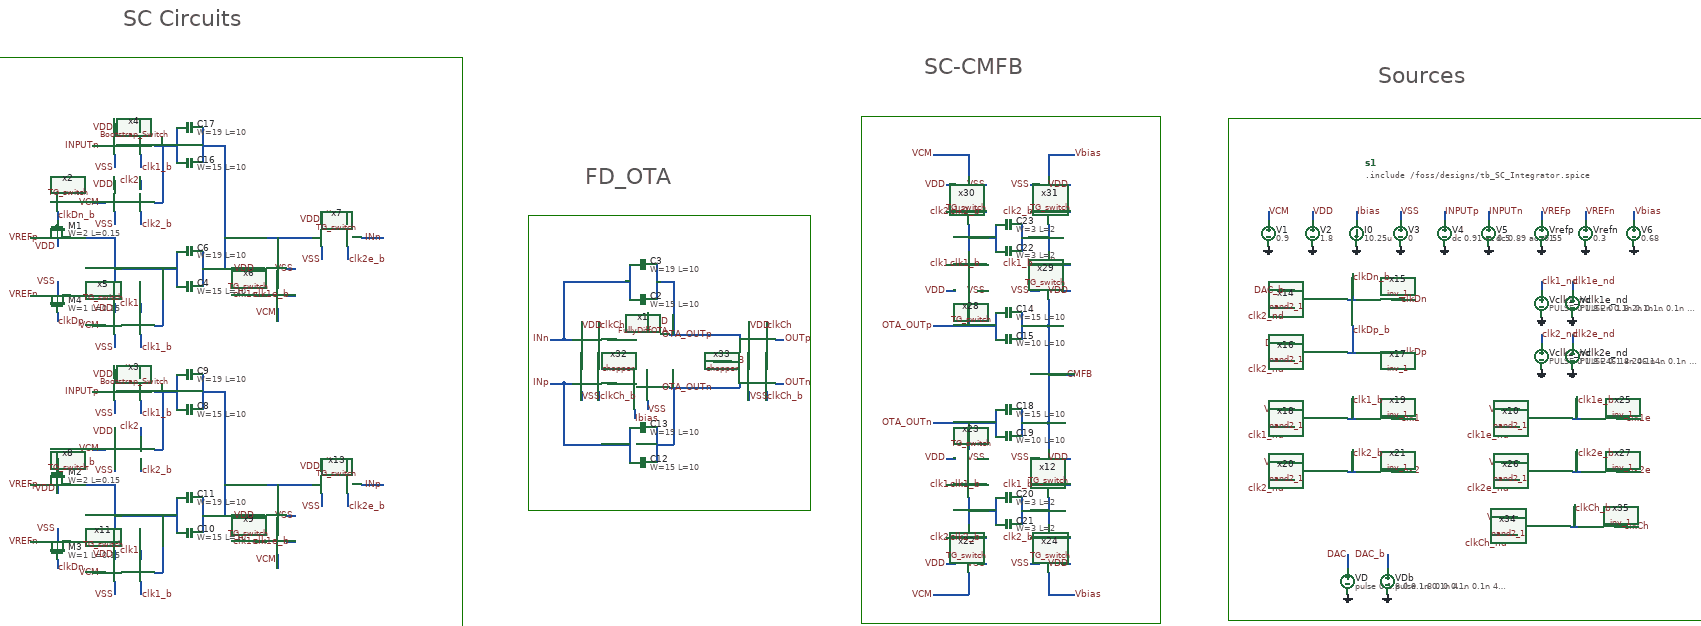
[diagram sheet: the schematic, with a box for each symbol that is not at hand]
v {xschem version=3.4.8RC file_version=1.3}
G {}
K {}
V {}
S {}
F {}
E {}
L 4 -1670 -770 -510 -770 {}
L 4 -510 -770 -510 570 {}
L 4 -1530 570 -510 570 {}
L 4 -1670 -770 -1670 570 {}
L 4 -1670 570 -1530 570 {}
P 4 5 1230 -630 2320 -630 2320 510 1230 510 1230 -630 {}
P 4 7 -360 -410 200 -410 280 -410 280 260 -330 260 -360 260 -360 -410 {}
P 4 5 395 -635 1075 -635 1075 515 395 515 395 -635 {}
T {Sources} 1570 -740 0 0 1.5 1.5 {}
T {FD_OTA} -230 -510 0 0 1.5 1.5 {}
T {SC Circuits} -1280 -870 0 0 1.5 1.5 {}
T {SC-CMFB} 540 -760 0 0 1.5 1.5 {}
N 1320 -420 1320 -400 {lab=VCM}
N 1420 -420 1420 -400 {lab=VDD}
N 1520 -420 1520 -400 {lab=Ibias}
N 1620 -420 1620 -400 {lab=VSS}
N 1720 -420 1720 -400 {lab=INPUTp}
N 1820 -420 1820 -400 {lab=INPUTn}
N 1940 -420 1940 -400 {lab=VREFp}
N 2040 -420 2040 -400 {lab=VREFn}
N 1500 -220 1520 -220 {lab=clkDn_b}
N 1340 -240 1380 -240 {lab=DAC_bar}
N 1360 -200 1380 -200 {lab=clk2_nd}
N 1360 -200 1360 -180 {lab=clk2_nd}
N 1600 -220 1630 -220 {lab=clkDn}
N 1340 -120 1380 -120 {lab=DAC}
N 1360 -80 1380 -80 {lab=clk2_nd}
N 1360 -80 1360 -60 {lab=clk2_nd}
N 1600 -100 1630 -100 {lab=clkDp}
N 1340 30 1380 30 {lab=VDD}
N 1360 70 1380 70 {lab=clk1_nd}
N 1360 70 1360 90 {lab=clk1_nd}
N 1600 50 1630 50 {lab=clk1}
N 1340 150 1380 150 {lab=VDD}
N 1360 190 1380 190 {lab=clk2_nd}
N 1360 190 1360 210 {lab=clk2_nd}
N 1600 170 1630 170 {lab=clk2}
N 1940 -260 1940 -240 {lab=clk1_nd}
N 2010 -260 2010 -240 {lab=clk1e_nd}
N 1850 30 1890 30 {lab=VDD}
N 1870 70 1890 70 {lab=clk1e_nd}
N 1870 70 1870 90 {lab=clk1e_nd}
N 2110 50 2140 50 {lab=clk1e}
N 1850 150 1890 150 {lab=VDD}
N 1870 190 1890 190 {lab=clk2e_nd}
N 1870 190 1870 210 {lab=clk2e_nd}
N 2110 170 2140 170 {lab=clk2e}
N 1940 -140 1940 -120 {lab=clk2_nd}
N 2010 -140 2010 -120 {lab=clk2e_nd}
N 1500 360 1500 390 {lab=DAC}
N 1590 360 1590 390 {lab=DAC_bar}
N 1500 -100 1520 -100 {lab=clkDp_b}
N 1500 50 1520 50 {lab=clk1_b}
N 1500 170 1520 170 {lab=clk2_b}
N 2010 50 2030 50 {lab=clk1e_b}
N 2010 170 2030 170 {lab=clk2e_b}
N 1510 0 1510 50 {lab=clk1_b}
N 1510 120 1510 170 {lab=clk2_b}
N 2020 0 2020 50 {lab=clk1e_b}
N 2020 120 2020 170 {lab=clk2e_b}
N 1510 -280 1510 -220 {lab=clkDn_b}
N 1510 -160 1510 -100 {lab=clkDp_b}
N 2150 -420 2150 -400 {lab=Vbias}
N 60 -80 100 -80 {lab=CMFB}
N -90 10 -90 30 {lab=VSS}
N -90 -190 -90 -170 {lab=VDD}
N -120 30 -120 50 {lab=Ibias}
N -40 -140 -20 -140 {lab=OTA_OUTp}
N -40 -20 -20 -20 {lab=OTA_OUTn}
N -1100 -570 -1050 -570 {lab=#net1}
N -1050 -550 -1050 -480 {lab=#net1}
N -1050 -570 -1050 -550 {lab=#net1}
N -1300 -550 -1300 -520 {lab=VSS}
N -1240 -620 -1240 -600 {lab=clk1}
N -1350 -570 -1320 -570 {lab=INPUTn}
N -1300 -420 -1300 -390 {lab=VSS}
N -1240 -490 -1240 -470 {lab=clk2}
N -1350 -440 -1320 -440 {lab=VCM}
N -1050 -480 -1050 -440 {lab=#net1}
N -1100 -290 -1050 -290 {lab=#net1}
N -1300 -140 -1300 -110 {lab=VSS}
N -1240 -210 -1240 -190 {lab=clk1}
N -1350 -160 -1320 -160 {lab=VCM}
N -1050 -440 -1050 -290 {lab=#net1}
N -1210 -570 -1160 -570 {lab=#net2}
N -1210 -290 -1160 -290 {lab=#net3}
N -1050 -360 -960 -360 {lab=#net1}
N -980 -230 -960 -230 {lab=clk1e}
N -930 -200 -930 -170 {lab=VCM}
N -930 -360 -930 -310 {lab=#net1}
N -960 -360 -940 -360 {lab=#net1}
N -940 -360 -850 -360 {lab=#net1}
N -830 -340 -830 -310 {lab=VSS}
N -770 -410 -770 -390 {lab=clk2e}
N -740 -360 -690 -360 {lab=INn}
N -170 -260 -130 -260 {lab=INn}
N -30 -220 -30 -140 {lab=OTA_OUTp}
N -30 -20 -30 70 {lab=OTA_OUTn}
N -180 -130 -160 -130 {lab=#net4}
N -180 -30 -160 -30 {lab=#net5}
N -20 -140 0 -140 {lab=OTA_OUTp}
N -20 -20 0 -20 {lab=OTA_OUTn}
N -1100 -10 -1050 -10 {lab=#net6}
N -1050 10 -1050 80 {lab=#net6}
N -1050 -10 -1050 10 {lab=#net6}
N -1300 10 -1300 40 {lab=VSS}
N -1240 -60 -1240 -40 {lab=clk1}
N -1350 -10 -1320 -10 {lab=INPUTp}
N -1300 140 -1300 170 {lab=VSS}
N -1240 70 -1240 90 {lab=clk2}
N -1350 120 -1320 120 {lab=VCM}
N -1050 80 -1050 120 {lab=#net6}
N -1100 270 -1050 270 {lab=#net6}
N -1300 420 -1300 450 {lab=VSS}
N -1240 350 -1240 370 {lab=clk1}
N -1350 400 -1320 400 {lab=VCM}
N -1050 120 -1050 270 {lab=#net6}
N -1210 -10 -1160 -10 {lab=#net7}
N -1210 270 -1160 270 {lab=#net8}
N -1050 200 -960 200 {lab=#net6}
N -930 200 -930 250 {lab=#net6}
N -960 200 -940 200 {lab=#net6}
N -940 200 -850 200 {lab=#net6}
N -830 220 -830 250 {lab=VSS}
N -770 150 -770 170 {lab=clk2e}
N -740 200 -690 200 {lab=INp}
N -1350 -360 -1300 -360 {lab=#net3}
N -1300 -360 -1300 -230 {lab=#net3}
N -1350 -230 -1300 -230 {lab=#net3}
N -1300 -290 -1210 -290 {lab=#net3}
N -1430 140 -1430 160 {lab=clkDp_b}
N -1490 200 -1460 200 {lab=VREFp}
N -1430 300 -1430 330 {lab=VSS}
N -1430 370 -1430 390 {lab=clkDn}
N -1490 330 -1460 330 {lab=VREFn}
N -1350 200 -1300 200 {lab=#net8}
N -1300 200 -1300 330 {lab=#net8}
N -1350 330 -1300 330 {lab=#net8}
N -1300 270 -1210 270 {lab=#net8}
N -1190 -570 -1190 -440 {lab=#net2}
N -1210 -440 -1190 -440 {lab=#net2}
N -1190 -10 -1190 120 {lab=#net7}
N -1210 120 -1190 120 {lab=#net7}
N -1210 400 -1190 400 {lab=#net8}
N -1190 270 -1190 400 {lab=#net8}
N -1190 -290 -1190 -160 {lab=#net3}
N -1210 -160 -1190 -160 {lab=#net3}
N -910 -290 -890 -290 {lab=VSS}
N -70 -260 -30 -260 {lab=OTA_OUTp}
N -30 -260 -30 -220 {lab=OTA_OUTp}
N -170 110 -130 110 {lab=INp}
N -30 70 -30 110 {lab=OTA_OUTn}
N -70 110 -30 110 {lab=OTA_OUTn}
N -1160 -610 -1160 -530 {lab=#net2}
N -1100 -610 -1100 -530 {lab=#net1}
N -1160 -330 -1160 -250 {lab=#net3}
N -1100 -330 -1100 -250 {lab=#net1}
N -1160 -50 -1160 30 {lab=#net7}
N -1100 -50 -1100 30 {lab=#net6}
N -1160 230 -1160 310 {lab=#net8}
N -1100 230 -1100 310 {lab=#net6}
N -130 -300 -130 -220 {lab=INn}
N -70 -300 -70 -220 {lab=OTA_OUTp}
N -130 70 -130 150 {lab=INp}
N -70 70 -70 150 {lab=OTA_OUTn}
N -1240 -550 -1240 -530 {lab=clk1_b}
N -1240 -530 -1240 -520 {lab=clk1_b}
N -1300 -620 -1300 -600 {lab=VDD}
N -1300 -60 -1300 -40 {lab=VDD}
N -1240 10 -1240 30 {lab=clk1_b}
N -1240 30 -1240 40 {lab=clk1_b}
N -1430 200 -1430 220 {lab=VDD}
N -1400 200 -1350 200 {lab=#net8}
N -1430 -420 -1430 -400 {lab=clkDn_b}
N -1490 -360 -1460 -360 {lab=VREFp}
N -1430 -360 -1430 -340 {lab=VDD}
N -1400 -360 -1350 -360 {lab=#net3}
N -1400 330 -1350 330 {lab=#net8}
N -1430 -260 -1430 -230 {lab=VSS}
N -1430 -190 -1430 -170 {lab=clkDp}
N -1490 -230 -1460 -230 {lab=VREFn}
N -1400 -230 -1350 -230 {lab=#net3}
N -980 -290 -960 -290 {lab=VDD}
N -910 -230 -890 -230 {lab=clk1e_b}
N -980 330 -960 330 {lab=clk1e}
N -930 360 -930 390 {lab=VCM}
N -910 270 -890 270 {lab=VSS}
N -980 270 -960 270 {lab=VDD}
N -910 330 -890 330 {lab=clk1e_b}
N -1300 -490 -1300 -470 {lab=VDD}
N -1300 -210 -1300 -190 {lab=VDD}
N -830 -410 -830 -390 {lab=VDD}
N -1300 70 -1300 90 {lab=VDD}
N -1300 350 -1300 370 {lab=VDD}
N -830 150 -830 170 {lab=VDD}
N -1240 -420 -1240 -390 {lab=clk2_b}
N -1240 -140 -1240 -110 {lab=clk1_b}
N -1240 140 -1240 170 {lab=clk2_b}
N -1240 420 -1240 450 {lab=clk1_b}
N -770 -340 -770 -310 {lab=clk2e_b}
N -770 220 -770 250 {lab=clk2e_b}
N 560 -160 580 -160 {lab=OTA_OUTp}
N 560 60 580 60 {lab=OTA_OUTn}
N 580 60 700 60 {lab=OTA_OUTn}
N 700 -190 700 -130 {lab=OTA_OUTp}
N 760 -190 760 -180 {lab=CMFB}
N 760 -180 760 -140 {lab=CMFB}
N 760 -140 760 -130 {lab=CMFB}
N 700 30 700 90 {lab=OTA_OUTn}
N 760 30 760 40 {lab=CMFB}
N 760 40 760 80 {lab=CMFB}
N 760 80 760 90 {lab=CMFB}
N 580 -160 700 -160 {lab=OTA_OUTp}
N 560 450 600 450 {lab=VCM}
N 590 200 610 200 {lab=clk1}
N 660 140 680 140 {lab=VSS}
N 590 140 610 140 {lab=VDD}
N 660 200 680 200 {lab=clk1_b}
N 640 60 640 120 {lab=OTA_OUTn}
N 850 200 870 200 {lab=clk1}
N 780 200 800 200 {lab=clk1_b}
N 820 60 820 120 {lab=CMFB}
N 850 140 870 140 {lab=VDD}
N 780 140 800 140 {lab=VSS}
N 590 320 610 320 {lab=clk2}
N 660 380 680 380 {lab=VSS}
N 590 380 610 380 {lab=VDD}
N 660 320 680 320 {lab=clk2_b}
N 850 320 870 320 {lab=clk2}
N 780 320 800 320 {lab=clk2_b}
N 850 380 870 380 {lab=VDD}
N 780 380 800 380 {lab=VSS}
N 600 450 640 450 {lab=VCM}
N 640 400 640 450 {lab=VCM}
N 820 450 880 450 {lab=Vbias}
N 820 400 820 450 {lab=Vbias}
N 640 230 640 290 {lab=#net9}
N 820 230 820 290 {lab=#net10}
N 700 230 700 290 {lab=#net9}
N 760 230 760 240 {lab=#net10}
N 760 240 760 280 {lab=#net10}
N 760 280 760 290 {lab=#net10}
N 640 260 700 260 {lab=#net9}
N 760 260 820 260 {lab=#net10}
N 560 -550 600 -550 {lab=VCM}
N 590 -300 610 -300 {lab=clk1}
N 660 -240 680 -240 {lab=VSS}
N 590 -240 610 -240 {lab=VDD}
N 660 -300 680 -300 {lab=clk1_b}
N 640 -220 640 -160 {lab=OTA_OUTp}
N 850 -300 870 -300 {lab=clk1}
N 780 -300 800 -300 {lab=clk1_b}
N 820 -220 820 -160 {lab=CMFB}
N 850 -240 870 -240 {lab=VDD}
N 780 -240 800 -240 {lab=VSS}
N 590 -420 610 -420 {lab=clk2}
N 660 -480 680 -480 {lab=VSS}
N 590 -480 610 -480 {lab=VDD}
N 660 -420 680 -420 {lab=clk2_b}
N 850 -420 870 -420 {lab=clk2}
N 780 -420 800 -420 {lab=clk2_b}
N 850 -480 870 -480 {lab=VDD}
N 780 -480 800 -480 {lab=VSS}
N 600 -550 640 -550 {lab=VCM}
N 640 -550 640 -500 {lab=VCM}
N 820 -550 880 -550 {lab=Vbias}
N 820 -550 820 -500 {lab=Vbias}
N 640 -390 640 -330 {lab=#net11}
N 820 -390 820 -330 {lab=#net12}
N 700 -390 700 -330 {lab=#net11}
N 760 -340 760 -330 {lab=#net12}
N 760 -380 760 -340 {lab=#net12}
N 760 -390 760 -380 {lab=#net12}
N 640 -360 700 -360 {lab=#net11}
N 760 -360 820 -360 {lab=#net12}
N 820 -160 820 60 {lab=CMFB}
N 820 -50 880 -50 {lab=CMFB}
N 760 60 820 60 {lab=CMFB}
N 760 -160 820 -160 {lab=CMFB}
N -280 -130 -260 -130 {lab=INn}
N -280 -30 -260 -30 {lab=INp}
N -280 -260 -170 -260 {lab=INn}
N -280 -260 -280 -130 {lab=INn}
N -280 -30 -280 110 {lab=INp}
N -280 110 -170 110 {lab=INp}
N -310 -30 -280 -30 {lab=INp}
N -310 -130 -280 -130 {lab=INn}
N 0 -140 120 -140 {lab=OTA_OUTp}
N 120 -140 120 -130 {lab=OTA_OUTp}
N 0 -20 120 -20 {lab=OTA_OUTn}
N 120 -30 120 -20 {lab=OTA_OUTn}
N 200 -130 220 -130 {lab=OUTp}
N 200 -30 220 -30 {lab=OUTn}
N -240 -170 -240 -150 {lab=VDD}
N -200 -170 -200 -150 {lab=clkCh}
N -240 -10 -240 10 {lab=VSS}
N -200 -10 -200 10 {lab=clkCh_b}
N 140 -170 140 -150 {lab=VDD}
N 180 -170 180 -150 {lab=clkCh}
N 140 -10 140 10 {lab=VSS}
N 180 -10 180 10 {lab=clkCh_b}
N 1845 275 1885 275 {lab=VDD}
N 1865 315 1885 315 {lab=clkCh_nd}
N 1865 315 1865 335 {lab=clkCh_nd}
N 2105 295 2135 295 {lab=clkCh}
N 2005 295 2025 295 {lab=clkCh_b}
N 2015 245 2015 295 {lab=clkCh_b}
C {vsource.sym} 1320 -370 0 0 {name=V1 value=0.9 savecurrent=false}
C {lab_wire.sym} 1420 -420 0 1 {name=p16 sig_type=std_logic lab=VDD}
C {vsource.sym} 1420 -370 0 0 {name=V2 value=1.8 savecurrent=false}
C {lab_wire.sym} 1520 -420 0 1 {name=p18 sig_type=std_logic lab=Ibias}
C {isource.sym} 1520 -370 0 0 {name=I0 value=10.25u}
C {lab_wire.sym} 1620 -420 0 1 {name=p21 sig_type=std_logic lab=VSS}
C {vsource.sym} 1620 -370 0 0 {name=V3 value=0 savecurrent=false
lab=VSS}
C {gnd.sym} 1320 -340 0 0 {name=l1 lab=0}
C {gnd.sym} 1420 -340 0 0 {name=l2 lab=0}
C {gnd.sym} 1520 -340 0 0 {name=l3 lab=0}
C {gnd.sym} 1620 -340 0 0 {name=l4 lab=0}
C {code_shown.sym} 1540 -530 0 0 {name=s1 only_toplevel=false value=".include /foss/designs/tb_SC_Integrator.spice"}
C {launcher.sym} 1340 -520 0 0 {name=h1
descr=backannotate
tclcommand="xschem annotate_op"}
C {lab_wire.sym} 1320 -420 0 1 {name=p11 sig_type=std_logic lab=VCM}
C {vsource.sym} 1720 -370 0 0 {name=V4 value="dc 0.91 ac 0.5" savecurrent=false
lab=INp}
C {vsource.sym} 1820 -370 0 0 {name=V5 value="dc 0.89 ac -0.5" savecurrent=false
lab=INn}
C {gnd.sym} 1720 -340 0 0 {name=l5 lab=0}
C {gnd.sym} 1820 -340 0 0 {name=l6 lab=0}
C {lab_wire.sym} 1820 -420 0 1 {name=p15 sig_type=std_logic lab=INPUTn}
C {lab_wire.sym} 1720 -420 0 1 {name=p17 sig_type=std_logic lab=INPUTp}
C {vsource.sym} 1940 -370 0 0 {name=Vrefp value=1.5 savecurrent=false}
C {gnd.sym} 1940 -340 0 0 {name=Vrefp1 lab=0}
C {lab_wire.sym} 1940 -420 0 1 {name=Vrefp2 sig_type=std_logic lab=VREFp}
C {vsource.sym} 2040 -370 0 0 {name=Vrefn value=0.3 savecurrent=false}
C {gnd.sym} 2040 -340 0 0 {name=Vrefp4 lab=0}
C {lab_wire.sym} 2040 -420 0 1 {name=Vrefp5 sig_type=std_logic lab=VREFn}
C {sky130_stdcells/nand2_1.sym} 1440 -220 0 0 {name=x14 VGND=VSS VNB=VSS VPB=VDD VPWR=VDD prefix=sky130_fd_sc_hd__ }
C {sky130_stdcells/inv_1.sym} 1560 -220 0 0 {name=x15 VGND=VSS VNB=VSS VPB=VDD VPWR=VDD prefix=sky130_fd_sc_hd__ }
C {lab_wire.sym} 1360 -180 0 0 {name=p23 sig_type=std_logic lab=clk2_nd}
C {lab_wire.sym} 1360 -240 0 0 {name=p24 sig_type=std_logic lab=DAC_b}
C {lab_wire.sym} 1360 -60 0 0 {name=p25 sig_type=std_logic lab=clk2_nd}
C {lab_wire.sym} 1360 -120 0 0 {name=p26 sig_type=std_logic lab=DAC}
C {lab_wire.sym} 1620 -220 2 0 {name=p32 sig_type=std_logic lab=clkDn}
C {lab_wire.sym} 1620 -100 2 0 {name=p33 sig_type=std_logic lab=clkDp}
C {lab_wire.sym} 1360 90 0 0 {name=p34 sig_type=std_logic lab=clk1_nd}
C {lab_wire.sym} 1360 30 0 0 {name=p35 sig_type=std_logic lab=VDD}
C {lab_wire.sym} 1360 210 0 0 {name=p36 sig_type=std_logic lab=clk2_nd}
C {lab_wire.sym} 1360 150 0 0 {name=p37 sig_type=std_logic lab=VDD}
C {lab_wire.sym} 1620 50 2 0 {name=p38 sig_type=std_logic lab=clk1}
C {lab_wire.sym} 1620 170 2 0 {name=p39 sig_type=std_logic lab=clk2}
C {vsource.sym} 1940 -210 0 1 {name=Vclk1_nd value="PULSE 0 1.8 2n 0.1n 0.1n 238n 488.28n" savecurrent=false}
C {gnd.sym} 1940 -180 0 0 {name=l7 lab=0}
C {lab_wire.sym} 1940 -260 0 1 {name=p58 sig_type=std_logic lab=clk1_nd}
C {vsource.sym} 2010 -210 0 0 {name=Vclk1e_nd value="PULSE 0 1.8 2n 0.1n 0.1n 237n 488.28n" savecurrent=false}
C {gnd.sym} 2010 -180 0 1 {name=l8 lab=0}
C {lab_wire.sym} 2010 -260 0 1 {name=p59 sig_type=std_logic lab=clk1e_nd}
C {lab_wire.sym} 1870 90 0 0 {name=p60 sig_type=std_logic lab=clk1e_nd}
C {lab_wire.sym} 1870 30 0 0 {name=p79 sig_type=std_logic lab=VDD}
C {lab_wire.sym} 1870 210 0 0 {name=p80 sig_type=std_logic lab=clk2e_nd}
C {lab_wire.sym} 1870 150 0 0 {name=p81 sig_type=std_logic lab=VDD}
C {lab_wire.sym} 2130 50 2 0 {name=p82 sig_type=std_logic lab=clk1e}
C {lab_wire.sym} 2130 170 2 0 {name=p83 sig_type=std_logic lab=clk2e}
C {vsource.sym} 1940 -90 0 1 {name=Vclk2_nd value="PULSE 0 1.8 246.14n 0.1n 0.1n 238n 488.28n" savecurrent=false}
C {gnd.sym} 1940 -60 0 0 {name=l9 lab=0}
C {lab_wire.sym} 1940 -140 0 1 {name=p84 sig_type=std_logic lab=clk2_nd}
C {vsource.sym} 2010 -90 0 0 {name=Vclk2e_nd value="PULSE 0 1.8 246.14n 0.1n 0.1n 237n 488.28n" savecurrent=false}
C {gnd.sym} 2010 -60 0 1 {name=l10 lab=0}
C {lab_wire.sym} 2010 -140 0 1 {name=p85 sig_type=std_logic lab=clk2e_nd}
C {lab_wire.sym} 1590 360 0 0 {name=p86 sig_type=std_logic lab=DAC_b}
C {lab_wire.sym} 1500 360 0 0 {name=p87 sig_type=std_logic lab=DAC}
C {vsource.sym} 1500 420 0 1 {name=VD value="pulse 0 1.8 0 0.1n 0.1n 488.18n 976.56n" savecurrent=false}
C {gnd.sym} 1500 450 0 0 {name=l11 lab=0}
C {vsource.sym} 1590 420 0 0 {name=VDb value="pulse 1.8 0 0 0.1n 0.1n 488.18n 976.56n" savecurrent=false}
C {gnd.sym} 1590 450 0 0 {name=l12 lab=0}
C {sky130_stdcells/nand2_1.sym} 1440 -100 0 0 {name=x16 VGND=VSS VNB=VSS VPB=VDD VPWR=VDD prefix=sky130_fd_sc_hd__ }
C {sky130_stdcells/inv_1.sym} 1560 -100 0 0 {name=x17 VGND=VSS VNB=VSS VPB=VDD VPWR=VDD prefix=sky130_fd_sc_hd__ }
C {sky130_stdcells/nand2_1.sym} 1440 50 0 0 {name=x18 VGND=VSS VNB=VSS VPB=VDD VPWR=VDD prefix=sky130_fd_sc_hd__ }
C {sky130_stdcells/inv_1.sym} 1560 50 0 0 {name=x19 VGND=VSS VNB=VSS VPB=VDD VPWR=VDD prefix=sky130_fd_sc_hd__ }
C {sky130_stdcells/nand2_1.sym} 1440 170 0 0 {name=x20 VGND=VSS VNB=VSS VPB=VDD VPWR=VDD prefix=sky130_fd_sc_hd__ }
C {sky130_stdcells/inv_1.sym} 1560 170 0 0 {name=x21 VGND=VSS VNB=VSS VPB=VDD VPWR=VDD prefix=sky130_fd_sc_hd__ }
C {sky130_stdcells/nand2_1.sym} 1950 50 0 0 {name=x10 VGND=VSS VNB=VSS VPB=VDD VPWR=VDD prefix=sky130_fd_sc_hd__ }
C {sky130_stdcells/inv_1.sym} 2070 50 0 0 {name=x25 VGND=VSS VNB=VSS VPB=VDD VPWR=VDD prefix=sky130_fd_sc_hd__ }
C {sky130_stdcells/nand2_1.sym} 1950 170 0 0 {name=x26 VGND=VSS VNB=VSS VPB=VDD VPWR=VDD prefix=sky130_fd_sc_hd__ }
C {sky130_stdcells/inv_1.sym} 2070 170 0 0 {name=x27 VGND=VSS VNB=VSS VPB=VDD VPWR=VDD prefix=sky130_fd_sc_hd__ }
C {lab_wire.sym} 1510 10 0 1 {name=p89 sig_type=std_logic lab=clk1_b}
C {lab_wire.sym} 1510 130 0 1 {name=p90 sig_type=std_logic lab=clk2_b}
C {lab_wire.sym} 2020 10 0 1 {name=p92 sig_type=std_logic lab=clk1e_b}
C {lab_wire.sym} 2020 130 0 1 {name=p93 sig_type=std_logic lab=clk2e_b}
C {lab_wire.sym} 1510 -150 0 1 {name=p70 sig_type=std_logic lab=clkDp_b}
C {lab_wire.sym} 1510 -270 0 1 {name=p71 sig_type=std_logic lab=clkDn_b}
C {lab_wire.sym} 2150 -420 0 1 {name=p9 sig_type=std_logic lab=Vbias}
C {vsource.sym} 2150 -370 0 0 {name=V6 value=0.68 savecurrent=false}
C {gnd.sym} 2150 -340 0 0 {name=l13 lab=0}
C {lab_wire.sym} -90 30 0 1 {name=p27 sig_type=std_logic lab=VSS}
C {lab_wire.sym} -90 -170 0 1 {name=p28 sig_type=std_logic lab=VDD}
C {lab_wire.sym} -120 50 0 1 {name=p29 sig_type=std_logic lab=Ibias}
C {lab_wire.sym} 70 -80 0 1 {name=p30 sig_type=std_logic lab=CMFB}
C {lab_wire.sym} -310 -30 3 0 {name=p2 sig_type=std_logic lab=INp}
C {lab_wire.sym} -310 -130 3 1 {name=p3 sig_type=std_logic lab=INn}
C {lab_wire.sym} 220 -130 0 1 {name=p4 sig_type=std_logic lab=OUTp}
C {lab_wire.sym} 220 -30 0 1 {name=p5 sig_type=std_logic lab=OUTn}
C {lab_wire.sym} -1300 -520 0 0 {name=p6 sig_type=std_logic lab=VSS}
C {lab_wire.sym} -1240 -620 2 1 {name=p7 sig_type=std_logic lab=clk1}
C {lab_wire.sym} -1330 -570 2 1 {name=p8 sig_type=std_logic lab=INPUTn}
C {lab_wire.sym} -1300 -390 0 0 {name=p47 sig_type=std_logic lab=VSS}
C {lab_wire.sym} -1240 -490 2 1 {name=p48 sig_type=std_logic lab=clk2}
C {lab_wire.sym} -1330 -440 2 1 {name=p49 sig_type=std_logic lab=VCM}
C {lab_wire.sym} -1300 -110 0 0 {name=p45 sig_type=std_logic lab=VSS}
C {lab_wire.sym} -1240 -210 2 1 {name=p46 sig_type=std_logic lab=clk1}
C {lab_wire.sym} -1330 -160 2 1 {name=p50 sig_type=std_logic lab=VCM}
C {lab_wire.sym} -890 -290 3 0 {name=p51 sig_type=std_logic lab=VSS}
C {lab_wire.sym} -970 -230 3 0 {name=p52 sig_type=std_logic lab=clk1e}
C {lab_wire.sym} -930 -190 1 1 {name=p53 sig_type=std_logic lab=VCM}
C {lab_wire.sym} -830 -310 0 0 {name=p54 sig_type=std_logic lab=VSS}
C {lab_wire.sym} -770 -410 2 1 {name=p55 sig_type=std_logic lab=clk2e}
C {lab_wire.sym} -690 -360 3 1 {name=p56 sig_type=std_logic lab=INn}
C {Analog/FullyDiffOTA.sym} -40 -260 0 0 {name=x1}
C {lab_wire.sym} -1300 40 0 0 {name=p31 sig_type=std_logic lab=VSS}
C {lab_wire.sym} -1240 -60 2 1 {name=p40 sig_type=std_logic lab=clk1}
C {lab_wire.sym} -1330 -10 2 1 {name=p41 sig_type=std_logic lab=INPUTp}
C {lab_wire.sym} -1300 170 0 0 {name=p42 sig_type=std_logic lab=VSS}
C {lab_wire.sym} -1240 70 2 1 {name=p43 sig_type=std_logic lab=clk2}
C {lab_wire.sym} -1330 120 2 1 {name=p57 sig_type=std_logic lab=VCM}
C {lab_wire.sym} -1300 450 0 0 {name=p61 sig_type=std_logic lab=VSS}
C {lab_wire.sym} -1240 350 2 1 {name=p62 sig_type=std_logic lab=clk1}
C {lab_wire.sym} -1330 400 2 1 {name=p63 sig_type=std_logic lab=VCM}
C {lab_wire.sym} -830 250 0 0 {name=p67 sig_type=std_logic lab=VSS}
C {lab_wire.sym} -770 150 2 1 {name=p68 sig_type=std_logic lab=clk2e}
C {lab_wire.sym} -690 200 3 1 {name=p69 sig_type=std_logic lab=INp}
C {lab_wire.sym} -1470 200 2 1 {name=p75 sig_type=std_logic lab=VREFp}
C {lab_wire.sym} -1430 300 3 1 {name=p76 sig_type=std_logic lab=VSS}
C {lab_wire.sym} -1430 390 0 1 {name=p77 sig_type=std_logic lab=clkDn}
C {lab_wire.sym} -1470 330 2 1 {name=p78 sig_type=std_logic lab=VREFn}
C {sky130_fd_pr/cap_mim_m3_2.sym} -1130 -530 1 1 {name=C16 model=cap_mim_m3_2 W=15 L=10 MF=3 spiceprefix=X}
C {sky130_fd_pr/cap_mim_m3_1.sym} -1130 -610 1 0 {name=C17 model=cap_mim_m3_1 W=19 L=10 MF=3 spiceprefix=X}
C {sky130_fd_pr/cap_mim_m3_2.sym} -100 -220 1 1 {name=C2 model=cap_mim_m3_2 W=15 L=10 MF=10 spiceprefix=X}
C {sky130_fd_pr/cap_mim_m3_1.sym} -100 -300 1 0 {name=C3 model=cap_mim_m3_1 W=19 L=10 MF=10 spiceprefix=X}
C {sky130_fd_pr/cap_mim_m3_2.sym} -1130 -250 1 1 {name=C4 model=cap_mim_m3_2 W=15 L=10 MF=3 spiceprefix=X}
C {sky130_fd_pr/cap_mim_m3_1.sym} -1130 -330 1 0 {name=C6 model=cap_mim_m3_1 W=19 L=10 MF=3 spiceprefix=X}
C {sky130_fd_pr/cap_mim_m3_2.sym} -1130 30 1 1 {name=C8 model=cap_mim_m3_2 W=15 L=10 MF=3 spiceprefix=X}
C {sky130_fd_pr/cap_mim_m3_1.sym} -1130 -50 1 0 {name=C9 model=cap_mim_m3_1 W=19 L=10 MF=3 spiceprefix=X}
C {sky130_fd_pr/cap_mim_m3_2.sym} -1130 310 1 1 {name=C10 model=cap_mim_m3_2 W=15 L=10 MF=3 spiceprefix=X}
C {sky130_fd_pr/cap_mim_m3_1.sym} -1130 230 1 0 {name=C11 model=cap_mim_m3_1 W=19 L=10 MF=3 spiceprefix=X}
C {sky130_fd_pr/cap_mim_m3_2.sym} -100 150 1 1 {name=C12 model=cap_mim_m3_2 W=15 L=10 MF=10 spiceprefix=X}
C {sky130_fd_pr/cap_mim_m3_1.sym} -100 70 1 0 {name=C13 model=cap_mim_m3_1 W=19 L=10 MF=10 spiceprefix=X}
C {lab_wire.sym} -1240 -520 0 1 {name=p91 sig_type=std_logic lab=clk1_b}
C {lab_wire.sym} -1300 -610 0 0 {name=p94 sig_type=std_logic lab=VDD}
C {lab_wire.sym} -1300 -50 0 0 {name=p95 sig_type=std_logic lab=VDD}
C {lab_wire.sym} -1240 40 0 1 {name=p96 sig_type=std_logic lab=clk1_b}
C {sky130_fd_pr/pfet_01v8.sym} -1430 180 1 0 {name=M2
W=2
L=0.15
nf=1
mult=1
ad="expr('int((@nf + 1)/2) * @W / @nf * 0.29')"
pd="expr('2*int((@nf + 1)/2) * (@W / @nf + 0.29)')"
as="expr('int((@nf + 2)/2) * @W / @nf * 0.29')"
ps="expr('2*int((@nf + 2)/2) * (@W / @nf + 0.29)')"
nrd="expr('0.29 / @W ')" nrs="expr('0.29 / @W ')"
sa=0 sb=0 sd=0
model=pfet_01v8
spiceprefix=X
}
C {lab_wire.sym} -1470 -360 2 1 {name=p44 sig_type=std_logic lab=VREFp}
C {sky130_fd_pr/pfet_01v8.sym} -1430 -380 1 0 {name=M1
W=2
L=0.15
nf=1
mult=1
ad="expr('int((@nf + 1)/2) * @W / @nf * 0.29')"
pd="expr('2*int((@nf + 1)/2) * (@W / @nf + 0.29)')"
as="expr('int((@nf + 2)/2) * @W / @nf * 0.29')"
ps="expr('2*int((@nf + 2)/2) * (@W / @nf + 0.29)')"
nrd="expr('0.29 / @W ')" nrs="expr('0.29 / @W ')"
sa=0 sb=0 sd=0
model=pfet_01v8
spiceprefix=X
}
C {lab_wire.sym} -1430 -340 1 1 {name=p73 sig_type=std_logic lab=VDD}
C {sky130_fd_pr/nfet_01v8.sym} -1430 350 3 0 {name=M3
W=1
L=0.15
nf=1 
mult=1
ad="expr('int((@nf + 1)/2) * @W / @nf * 0.29')"
pd="expr('2*int((@nf + 1)/2) * (@W / @nf + 0.29)')"
as="expr('int((@nf + 2)/2) * @W / @nf * 0.29')"
ps="expr('2*int((@nf + 2)/2) * (@W / @nf + 0.29)')"
nrd="expr('0.29 / @W ')" nrs="expr('0.29 / @W ')"
sa=0 sb=0 sd=0
model=nfet_01v8
spiceprefix=X
}
C {lab_wire.sym} -1430 -260 3 1 {name=p1 sig_type=std_logic lab=VSS}
C {lab_wire.sym} -1430 -170 0 1 {name=p98 sig_type=std_logic lab=clkDp}
C {lab_wire.sym} -1470 -230 2 1 {name=p99 sig_type=std_logic lab=VREFn}
C {sky130_fd_pr/nfet_01v8.sym} -1430 -210 3 0 {name=M4
W=1
L=0.15
nf=1 
mult=1
ad="expr('int((@nf + 1)/2) * @W / @nf * 0.29')"
pd="expr('2*int((@nf + 1)/2) * (@W / @nf + 0.29)')"
as="expr('int((@nf + 2)/2) * @W / @nf * 0.29')"
ps="expr('2*int((@nf + 2)/2) * (@W / @nf + 0.29)')"
nrd="expr('0.29 / @W ')" nrs="expr('0.29 / @W ')"
sa=0 sb=0 sd=0
model=nfet_01v8
spiceprefix=X
}
C {lab_wire.sym} -1430 -410 0 1 {name=p20 sig_type=std_logic lab=clkDn_b}
C {lab_wire.sym} -1430 150 0 1 {name=p72 sig_type=std_logic lab=clkDp_b}
C {Analog/Bootstrap_Switch.sym} -1270 -570 0 0 {name=x4 Wn=1.0 Wp=1.0 LL=0.15}
C {Analog/Bootstrap_Switch.sym} -1270 -10 0 0 {name=x3 Wn=1.0 Wp=1.0 LL=0.15}
C {Analog/TG_switch.sym} -930 -260 3 1 {name=x6 Wn=3.0 Wp=10.0 LL=0.35}
C {lab_wire.sym} -980 -290 1 1 {name=p74 sig_type=std_logic lab=VDD}
C {lab_wire.sym} -900 -230 1 1 {name=p97 sig_type=std_logic lab=clk1e_b}
C {lab_wire.sym} -890 270 3 0 {name=p64 sig_type=std_logic lab=VSS}
C {lab_wire.sym} -970 330 3 0 {name=p65 sig_type=std_logic lab=clk1e}
C {lab_wire.sym} -930 370 1 1 {name=p66 sig_type=std_logic lab=VCM}
C {Analog/TG_switch.sym} -930 300 3 1 {name=x9 Wn=3.0 Wp=10.0 LL=0.35}
C {lab_wire.sym} -980 270 1 1 {name=p100 sig_type=std_logic lab=VDD}
C {lab_wire.sym} -900 330 1 1 {name=p101 sig_type=std_logic lab=clk1e_b}
C {lab_wire.sym} -1300 -480 0 0 {name=p102 sig_type=std_logic lab=VDD}
C {lab_wire.sym} -1300 -200 0 0 {name=p103 sig_type=std_logic lab=VDD}
C {lab_wire.sym} -830 -400 0 0 {name=p104 sig_type=std_logic lab=VDD}
C {lab_wire.sym} -1300 80 0 0 {name=p105 sig_type=std_logic lab=VDD}
C {lab_wire.sym} -1300 360 0 0 {name=p106 sig_type=std_logic lab=VDD}
C {lab_wire.sym} -830 160 0 0 {name=p107 sig_type=std_logic lab=VDD}
C {Analog/TG_switch.sym} -1270 -440 0 0 {name=x2 Wn=3.0 Wp=10.0 LL=0.35}
C {Analog/TG_switch.sym} -1270 -160 0 0 {name=x5 Wn=3.0 Wp=10.0 LL=0.35}
C {Analog/TG_switch.sym} -1270 120 0 0 {name=x8 Wn=3.0 Wp=10.0 LL=0.35}
C {Analog/TG_switch.sym} -1270 400 0 0 {name=x11 Wn=3.0 Wp=10.0 LL=0.35}
C {lab_wire.sym} -1240 -390 0 1 {name=p109 sig_type=std_logic lab=clk2_b}
C {lab_wire.sym} -1240 -110 0 1 {name=p111 sig_type=std_logic lab=clk1_b}
C {lab_wire.sym} -1240 170 0 1 {name=p112 sig_type=std_logic lab=clk2_b}
C {lab_wire.sym} -1240 450 0 1 {name=p113 sig_type=std_logic lab=clk1_b}
C {Analog/TG_switch.sym} -800 -360 0 0 {name=x7 Wn=4.0 Wp=14.0 LL=0.35}
C {Analog/TG_switch.sym} -800 200 0 0 {name=x13 Wn=4.0 Wp=14.0 LL=0.35}
C {lab_wire.sym} -770 -310 0 1 {name=p114 sig_type=std_logic lab=clk2e_b}
C {lab_wire.sym} -770 250 0 1 {name=p115 sig_type=std_logic lab=clk2e_b}
C {lab_wire.sym} -1430 210 1 1 {name=p116 sig_type=std_logic lab=VDD}
C {lab_wire.sym} 560 -160 0 0 {name=p108 sig_type=std_logic lab=OTA_OUTp}
C {lab_wire.sym} 560 450 0 0 {name=p117 sig_type=std_logic lab=VCM}
C {lab_wire.sym} 860 -50 0 1 {name=p118 sig_type=std_logic lab=CMFB}
C {lab_wire.sym} 560 60 2 1 {name=p120 sig_type=std_logic lab=OTA_OUTn}
C {sky130_fd_pr/cap_mim_m3_2.sym} 730 -190 1 0 {name=C14 model=cap_mim_m3_2 W=15 L=10 MF=1 spiceprefix=X}
C {sky130_fd_pr/cap_mim_m3_1.sym} 730 -130 1 1 {name=C15 model=cap_mim_m3_1 W=10 L=10 MF=1 spiceprefix=X}
C {sky130_fd_pr/cap_mim_m3_2.sym} 730 30 1 0 {name=C18 model=cap_mim_m3_2 W=15 L=10 MF=1 spiceprefix=X}
C {sky130_fd_pr/cap_mim_m3_1.sym} 730 90 1 1 {name=C19 model=cap_mim_m3_1 W=10 L=10 MF=1 spiceprefix=X}
C {lab_wire.sym} 880 450 2 0 {name=p110 sig_type=std_logic lab=Vbias}
C {lab_wire.sym} 680 140 3 0 {name=p119 sig_type=std_logic lab=VSS}
C {lab_wire.sym} 600 200 3 0 {name=p122 sig_type=std_logic lab=clk1}
C {Analog/TG_switch.sym} 640 170 3 1 {name=x23 Wn=3.0 Wp=10.0 LL=0.35}
C {lab_wire.sym} 590 140 1 1 {name=p124 sig_type=std_logic lab=VDD}
C {lab_wire.sym} 670 200 1 1 {name=p125 sig_type=std_logic lab=clk1_b}
C {lab_wire.sym} 780 140 1 1 {name=p123 sig_type=std_logic lab=VSS}
C {lab_wire.sym} 860 200 1 1 {name=p126 sig_type=std_logic lab=clk1}
C {Analog/TG_switch.sym} 820 170 1 0 {name=x12 Wn=3.0 Wp=10.0 LL=0.35}
C {lab_wire.sym} 870 140 3 0 {name=p127 sig_type=std_logic lab=VDD}
C {lab_wire.sym} 790 200 3 0 {name=p128 sig_type=std_logic lab=clk1_b}
C {lab_wire.sym} 680 380 3 1 {name=p129 sig_type=std_logic lab=VSS}
C {lab_wire.sym} 600 320 3 1 {name=p130 sig_type=std_logic lab=clk2}
C {Analog/TG_switch.sym} 640 350 3 0 {name=x22 Wn=3.0 Wp=10.0 LL=0.35}
C {lab_wire.sym} 590 380 1 0 {name=p131 sig_type=std_logic lab=VDD}
C {lab_wire.sym} 670 320 1 0 {name=p132 sig_type=std_logic lab=clk2_b}
C {lab_wire.sym} 780 380 1 0 {name=p133 sig_type=std_logic lab=VSS}
C {lab_wire.sym} 860 320 1 0 {name=p134 sig_type=std_logic lab=clk2}
C {Analog/TG_switch.sym} 820 350 1 1 {name=x24 Wn=3.0 Wp=10.0 LL=0.35}
C {lab_wire.sym} 870 380 3 1 {name=p135 sig_type=std_logic lab=VDD}
C {lab_wire.sym} 790 320 3 1 {name=p136 sig_type=std_logic lab=clk2_b}
C {sky130_fd_pr/cap_mim_m3_2.sym} 730 230 1 0 {name=C20 model=cap_mim_m3_2 W=3 L=2 MF=5 spiceprefix=X}
C {sky130_fd_pr/cap_mim_m3_1.sym} 730 290 1 1 {name=C21 model=cap_mim_m3_1 W=3 L=2 MF=5 spiceprefix=X}
C {lab_wire.sym} 560 -550 2 1 {name=p137 sig_type=std_logic lab=VCM}
C {lab_wire.sym} 880 -550 0 1 {name=p138 sig_type=std_logic lab=Vbias}
C {lab_wire.sym} 680 -240 3 1 {name=p139 sig_type=std_logic lab=VSS}
C {lab_wire.sym} 600 -300 3 1 {name=p140 sig_type=std_logic lab=clk1}
C {Analog/TG_switch.sym} 640 -270 3 0 {name=x28 Wn=3.0 Wp=10.0 LL=0.35}
C {lab_wire.sym} 590 -240 1 0 {name=p141 sig_type=std_logic lab=VDD}
C {lab_wire.sym} 670 -300 1 0 {name=p142 sig_type=std_logic lab=clk1_b}
C {lab_wire.sym} 780 -240 1 0 {name=p143 sig_type=std_logic lab=VSS}
C {lab_wire.sym} 860 -300 1 0 {name=p144 sig_type=std_logic lab=clk1}
C {Analog/TG_switch.sym} 820 -270 1 1 {name=x29 Wn=3.0 Wp=10.0 LL=0.35}
C {lab_wire.sym} 870 -240 3 1 {name=p145 sig_type=std_logic lab=VDD}
C {lab_wire.sym} 790 -300 3 1 {name=p146 sig_type=std_logic lab=clk1_b}
C {lab_wire.sym} 680 -480 3 0 {name=p147 sig_type=std_logic lab=VSS}
C {lab_wire.sym} 600 -420 3 0 {name=p148 sig_type=std_logic lab=clk2}
C {Analog/TG_switch.sym} 640 -450 3 1 {name=x30 Wn=3.0 Wp=10.0 LL=0.35}
C {lab_wire.sym} 590 -480 1 1 {name=p149 sig_type=std_logic lab=VDD}
C {lab_wire.sym} 670 -420 1 1 {name=p150 sig_type=std_logic lab=clk2_b}
C {lab_wire.sym} 780 -480 1 1 {name=p151 sig_type=std_logic lab=VSS}
C {lab_wire.sym} 860 -420 1 1 {name=p152 sig_type=std_logic lab=clk2}
C {Analog/TG_switch.sym} 820 -450 1 0 {name=x31 Wn=3.0 Wp=10.0 LL=0.35}
C {lab_wire.sym} 870 -480 3 0 {name=p153 sig_type=std_logic lab=VDD}
C {lab_wire.sym} 790 -420 3 0 {name=p154 sig_type=std_logic lab=clk2_b}
C {sky130_fd_pr/cap_mim_m3_2.sym} 730 -330 1 1 {name=C22 model=cap_mim_m3_2 W=3 L=2 MF=5 spiceprefix=X}
C {sky130_fd_pr/cap_mim_m3_1.sym} 730 -390 1 0 {name=C23 model=cap_mim_m3_1 W=3 L=2 MF=5 spiceprefix=X}
C {Analog/chopper.sym} -220 -80 0 0 {name=x32}
C {Analog/chopper.sym} 160 -80 0 0 {name=x33}
C {lab_wire.sym} 60 -140 0 0 {name=p10 sig_type=std_logic lab=OTA_OUTp}
C {lab_wire.sym} 60 -20 2 1 {name=p12 sig_type=std_logic lab=OTA_OUTn}
C {lab_wire.sym} -240 -160 0 1 {name=p13 sig_type=std_logic lab=VDD}
C {lab_wire.sym} -240 0 2 0 {name=p14 sig_type=std_logic lab=VSS}
C {lab_wire.sym} 140 -160 0 1 {name=p19 sig_type=std_logic lab=VDD}
C {lab_wire.sym} 140 0 2 0 {name=p22 sig_type=std_logic lab=VSS}
C {lab_wire.sym} -200 -160 0 1 {name=p88 sig_type=std_logic lab=clkCh}
C {lab_wire.sym} 180 -160 0 1 {name=p121 sig_type=std_logic lab=clkCh}
C {lab_wire.sym} -200 0 2 0 {name=p155 sig_type=std_logic lab=clkCh_b}
C {lab_wire.sym} 180 0 2 0 {name=p156 sig_type=std_logic lab=clkCh_b}
C {lab_wire.sym} 1865 335 0 0 {name=p157 sig_type=std_logic lab=clkCh_nd}
C {lab_wire.sym} 1865 275 0 0 {name=p158 sig_type=std_logic lab=VDD}
C {lab_wire.sym} 2125 295 2 0 {name=p159 sig_type=std_logic lab=clkCh}
C {sky130_stdcells/nand2_1.sym} 1945 295 0 0 {name=x34 VGND=VSS VNB=VSS VPB=VDD VPWR=VDD prefix=sky130_fd_sc_hd__ }
C {sky130_stdcells/inv_1.sym} 2065 295 0 0 {name=x35 VGND=VSS VNB=VSS VPB=VDD VPWR=VDD prefix=sky130_fd_sc_hd__ }
C {lab_wire.sym} 2015 255 0 1 {name=p160 sig_type=std_logic lab=clkCh_b}
